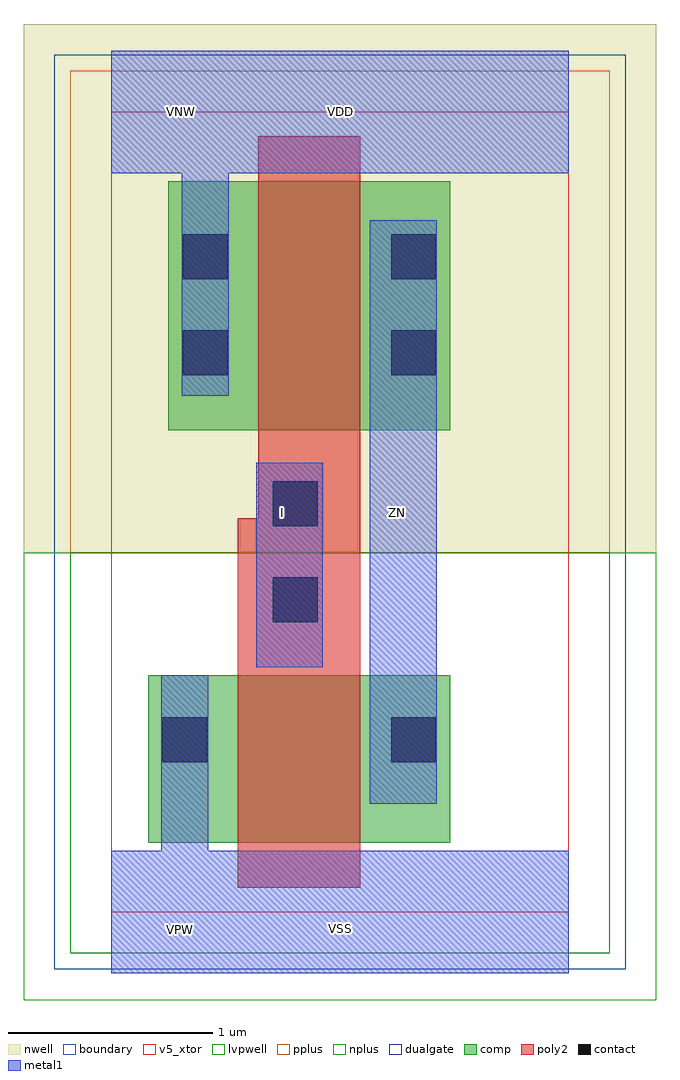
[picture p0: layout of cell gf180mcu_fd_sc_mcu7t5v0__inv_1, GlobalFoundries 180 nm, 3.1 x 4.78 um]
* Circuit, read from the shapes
.subckt gf180mcu_fd_sc_mcu7t5v0__inv_1 I VDD VNW VSS ZN
XM1 ZN I VSS VSUBS nfet_05v0 w=0.82u l=0.6u
XM2 ZN I VDD VNW pfet_05v0 w=1.22u l=0.5u
.ends

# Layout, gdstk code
import gdstk
lib = gdstk.Library(unit=1e-6, precision=5e-09)
def R(c, l, rs):  # rectangles x0, y0, x1, y1
    for r in rs: c.add(gdstk.rectangle(r[:2], r[2:], *l))
def P(c, l, *ps):  # polygons
    for p in ps: c.add(gdstk.Polygon(p, *l))
boundary = (0, 0)
nwell = (21, 0)
comp = (22, 0)
poly2 = (30, 0)
pplus = (31, 0)
nplus = (32, 0)
contact = (33, 0)
metal1 = (34, 0)
dualgate = (55, 0)
v5_xtor = (112, 1)
lvpwell = (204, 0)

gf180mcu_fd_sc_mcu7t5v0_ = lib.new_cell('gf180mcu_fd_sc_mcu7t5v0__inv_1')
R(gf180mcu_fd_sc_mcu7t5v0_, boundary, [(6.915,20.075,9.155,23.995)])
R(gf180mcu_fd_sc_mcu7t5v0_, nwell, [(6.485,21.835,9.585,24.425)])
R(gf180mcu_fd_sc_mcu7t5v0_, comp, [(7.095,20.415,8.575,21.235), (7.195,22.435,8.575,23.655)])
P(gf180mcu_fd_sc_mcu7t5v0_, poly2, [(7.535,20.195),(7.535,22.005),(7.635,22.005),(7.635,23.875),(8.135,23.875),(8.135,20.195)])
R(gf180mcu_fd_sc_mcu7t5v0_, pplus, [(6.715,21.835,9.355,24.195)])
R(gf180mcu_fd_sc_mcu7t5v0_, nplus, [(6.715,19.875,9.355,21.835)])
R(gf180mcu_fd_sc_mcu7t5v0_, contact, [(7.165,20.81,7.385,21.03), (8.285,20.81,8.505,21.03), (7.705,21.495,7.925,21.715), (7.705,21.965,7.925,22.185), (7.265,22.705,7.485,22.925), (8.285,22.705,8.505,22.925), (7.265,23.175,7.485,23.395), (8.285,23.175,8.505,23.395)])
R(gf180mcu_fd_sc_mcu7t5v0_, metal1, [(8.18,20.605,8.51,23.465), (7.625,21.275,7.95,22.275)])
P(gf180mcu_fd_sc_mcu7t5v0_, metal1, [(7.26,22.605),(7.26,23.695),(6.915,23.695),(6.915,24.295),(9.155,24.295),(9.155,23.695),(7.49,23.695),(7.49,22.605)],
  [(6.915,19.775),(6.915,20.375),(7.16,20.375),(7.16,21.235),(7.39,21.235),(7.39,20.375),(9.155,20.375),(9.155,19.775)])
R(gf180mcu_fd_sc_mcu7t5v0_, dualgate, [(6.635,19.795,9.435,24.275)])
R(gf180mcu_fd_sc_mcu7t5v0_, v5_xtor, [(6.915,20.075,9.155,23.995)])
R(gf180mcu_fd_sc_mcu7t5v0_, lvpwell, [(6.485,19.645,9.585,21.835)])
gf180mcu_fd_sc_mcu7t5v0_.add(gdstk.Label('VDD', (8.035,23.995), layer=34, texttype=10))
gf180mcu_fd_sc_mcu7t5v0_.add(gdstk.Label('I', (7.755,22.035), layer=34, texttype=10))
gf180mcu_fd_sc_mcu7t5v0_.add(gdstk.Label('ZN', (8.315,22.035), layer=34, texttype=10))
gf180mcu_fd_sc_mcu7t5v0_.add(gdstk.Label('VSS', (8.035,19.995), layer=34, texttype=10))
gf180mcu_fd_sc_mcu7t5v0_.add(gdstk.Label('VNW', (7.26,23.995), layer=21, texttype=10))
gf180mcu_fd_sc_mcu7t5v0_.add(gdstk.Label('VPW', (7.255,19.99), layer=204, texttype=10))

lib.write_gds('gf180mcu_fd_sc_mcu7t5v0__inv_1.gds')
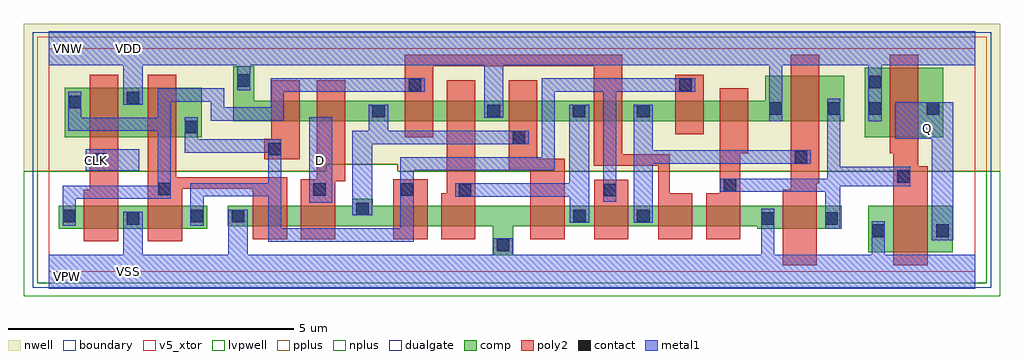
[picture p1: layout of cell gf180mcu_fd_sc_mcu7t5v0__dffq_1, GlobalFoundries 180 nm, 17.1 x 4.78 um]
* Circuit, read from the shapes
.subckt gf180mcu_fd_sc_mcu7t5v0__dffq_1 CLK D Q VDD VNW VSS
XM1 VSS CLK n1 VSUBS nfet_05v0 w=0.405u l=0.6u
XM2 n2 n1 VSS VSUBS nfet_05v0 w=0.405u l=0.6u
XM3 n3 n1 VSS VSUBS nfet_05v0 w=0.36u l=0.6u
XM4 n4 D n3 VSUBS nfet_05v0 w=0.36u l=0.6u
XM5 n5 n2 n4 VSUBS nfet_05v0 w=0.36u l=0.6u
XM6 VSS n6 n5 VSUBS nfet_05v0 w=0.36u l=0.6u
XM7 n6 n4 VSS VSUBS nfet_05v0 w=0.36u l=0.6u
XM8 n7 n2 n6 VSUBS nfet_05v0 w=0.36u l=0.6u
XM9 n8 n1 n7 VSUBS nfet_05v0 w=0.36u l=0.6u
XM10 VSS n9 n8 VSUBS nfet_05v0 w=0.36u l=0.6u
XM11 n9 n7 VSS VSUBS nfet_05v0 w=0.4u l=0.6u
XM12 Q n9 VSS VSUBS nfet_05v0 w=0.82u l=0.6u
XM13 VDD CLK n1 VNW pfet_05v0 w=0.865u l=0.5u
XM14 n2 n1 VDD VNW pfet_05v0 w=0.865u l=0.5u
XM15 n10 n2 VDD VNW pfet_05v0 w=0.36u l=0.5u
XM16 n4 D n10 VNW pfet_05v0 w=0.36u l=0.5u
XM17 n11 n1 n4 VNW pfet_05v0 w=0.36u l=0.5u
XM18 VDD n6 n11 VNW pfet_05v0 w=0.36u l=0.5u
XM19 n6 n4 VDD VNW pfet_05v0 w=0.36u l=0.5u
XM20 n7 n1 n6 VNW pfet_05v0 w=0.36u l=0.5u
XM21 n12 n2 n7 VNW pfet_05v0 w=0.36u l=0.5u
XM22 VDD n9 n12 VNW pfet_05v0 w=0.36u l=0.5u
XM23 n9 n7 VDD VNW pfet_05v0 w=0.8u l=0.5u
XM24 Q n9 VDD VNW pfet_05v0 w=1.22u l=0.5u
.ends

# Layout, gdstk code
import gdstk
lib = gdstk.Library(unit=1e-6, precision=5e-09)
def R(c, l, rs):  # rectangles x0, y0, x1, y1
    for r in rs: c.add(gdstk.rectangle(r[:2], r[2:], *l))
def P(c, l, *ps):  # polygons
    for p in ps: c.add(gdstk.Polygon(p, *l))
boundary = (0, 0)
nwell = (21, 0)
comp = (22, 0)
poly2 = (30, 0)
pplus = (31, 0)
nplus = (32, 0)
contact = (33, 0)
metal1 = (34, 0)
dualgate = (55, 0)
v5_xtor = (112, 1)
lvpwell = (204, 0)

gf180mcu_fd_sc_mcu7t5v0_ = lib.new_cell('gf180mcu_fd_sc_mcu7t5v0__dffq_1')
R(gf180mcu_fd_sc_mcu7t5v0_, boundary, [(-19.37,19.2,-3.13,23.12)])
P(gf180mcu_fd_sc_mcu7t5v0_, nwell, [(-19.8,20.96),(-19.8,23.55),(-2.7,23.55),(-2.7,20.96),(-13.25,20.96),(-13.25,21.085),(-14.505,21.085),(-14.505,20.96)])
R(gf180mcu_fd_sc_mcu7t5v0_, comp, [(-5.01,19.54,-3.53,20.36), (-19.19,19.955,-16.59,20.36), (-19.09,21.56,-16.69,22.425), (-5.07,21.56,-3.69,22.78)])
P(gf180mcu_fd_sc_mcu7t5v0_, comp, [(-16.13,21.835),(-16.13,22.8),(-15.77,22.8),(-15.77,22.195),(-6.81,22.195),(-6.81,22.635),(-5.43,22.635),(-5.43,21.835)],
  [(-11.59,19.49),(-11.59,19.995),(-16.23,19.995),(-16.23,20.355),(-14.05,20.355),(-14.05,20.485),(-13.69,20.485),(-13.69,20.355),(-5.47,20.355),(-5.47,19.955),(-6.95,19.955),(-6.95,19.995),(-11.23,19.995),(-11.23,19.49)])
R(gf180mcu_fd_sc_mcu7t5v0_, poly2, [(-13.33,19.775,-12.73,20.82), (-9.81,19.775,-9.21,20.815), (-8.39,21.615,-7.89,22.655)])
P(gf180mcu_fd_sc_mcu7t5v0_, poly2, [(-4.57,19.32),(-4.57,21.28),(-4.63,21.28),(-4.63,23),(-4.13,23),(-4.13,21.05),(-3.97,21.05),(-3.97,19.32)],
  [(-6.51,19.32),(-6.51,20.64),(-6.37,20.64),(-6.37,23),(-5.87,23),(-5.87,20.755),(-5.91,20.755),(-5.91,19.32)],
  [(-7.85,19.775),(-7.85,20.575),(-7.61,20.575),(-7.61,22.415),(-7.11,22.415),(-7.11,21.28),(-7.25,21.28),(-7.25,19.775)],
  [(-8.69,19.775),(-8.69,21.06),(-9.815,21.06),(-9.815,22.8),(-12.63,22.8),(-12.63,21.555),(-13.13,21.555),(-13.13,23),(-9.315,23),(-9.315,21.26),(-8.49,21.26),(-8.49,20.575),(-8.09,20.575),(-8.09,19.775)],
  [(-10.93,19.775),(-10.93,20.98),(-11.31,20.98),(-11.31,22.56),(-10.81,22.56),(-10.81,21.18),(-10.33,21.18),(-10.33,19.775)],
  [(-12.49,19.775),(-12.49,20.575),(-12.39,20.575),(-12.39,22.56),(-11.89,22.56),(-11.89,19.775)],
  [(-14.95,19.775),(-14.95,20.82),(-14.67,20.82),(-14.67,22.56),(-14.17,22.56),(-14.17,20.785),(-14.35,20.785),(-14.35,19.775)],
  [(-15.59,21.175),(-15.59,21.535),(-15.47,21.535),(-15.47,22.56),(-14.97,22.56),(-14.97,21.175)],
  [(-17.63,19.735),(-17.63,22.65),(-17.13,22.65),(-17.13,20.86),(-15.19,20.86),(-15.19,19.775),(-15.79,19.775),(-15.79,20.66),(-17.03,20.66),(-17.03,19.735)],
  [(-18.75,19.735),(-18.75,20.64),(-18.65,20.64),(-18.65,22.65),(-18.15,22.65),(-18.15,19.735)])
P(gf180mcu_fd_sc_mcu7t5v0_, pplus, [(-19.57,20.96),(-19.57,23.32),(-2.93,23.32),(-2.93,20.96),(-13.25,20.96),(-13.25,21.085),(-14.505,21.085),(-14.505,20.96)])
P(gf180mcu_fd_sc_mcu7t5v0_, nplus, [(-19.57,19),(-19.57,20.96),(-14.505,20.96),(-14.505,21.085),(-13.25,21.085),(-13.25,20.96),(-2.93,20.96),(-2.93,19)])
R(gf180mcu_fd_sc_mcu7t5v0_, contact, [(-11.52,19.56,-11.3,19.78), (-4.94,19.81,-4.72,20.03), (-3.82,19.81,-3.6,20.03), (-18,20.025,-17.78,20.245), (-6.88,20.025,-6.66,20.245), (-5.76,20.025,-5.54,20.245), (-16.16,20.065,-15.94,20.285), (-10.18,20.065,-9.96,20.285), (-9.06,20.065,-8.84,20.285), (-19.12,20.07,-18.9,20.29), (-16.88,20.07,-16.66,20.29), (-13.98,20.195,-13.76,20.415), (-12.18,20.525,-11.96,20.745), (-9.645,20.525,-9.425,20.745), (-14.735,20.53,-14.515,20.75), (-13.2,20.53,-12.98,20.75), (-17.45,20.54,-17.23,20.76), (-7.54,20.605,-7.32,20.825), (-4.5,20.76,-4.28,20.98), (-18.58,21.055,-18.36,21.275), (-6.3,21.1,-6.08,21.32), (-15.52,21.245,-15.3,21.465), (-11.24,21.445,-11.02,21.665), (-16.98,21.63,-16.76,21.85), (-13.7,21.905,-13.48,22.125), (-11.68,21.905,-11.46,22.125), (-10.185,21.905,-9.965,22.125), (-9.06,21.905,-8.84,22.125), (-6.74,21.95,-6.52,22.17), (-5.72,21.95,-5.5,22.17), (-5,21.95,-4.78,22.17), (-3.98,21.95,-3.76,22.17), (-19.02,22.07,-18.8,22.29), (-18,22.135,-17.78,22.355), (-13.06,22.365,-12.84,22.585), (-8.32,22.365,-8.1,22.585), (-5,22.42,-4.78,22.64), (-16.06,22.445,-15.84,22.665)])
R(gf180mcu_fd_sc_mcu7t5v0_, metal1, [(-14.8,20.41,-14.395,21.91), (-18.72,20.97,-17.78,21.35)])
P(gf180mcu_fd_sc_mcu7t5v0_, metal1, [(-6.745,21.835),(-6.745,22.82),(-11.4,22.82),(-11.4,21.9),(-11.74,21.9),(-11.74,22.82),(-15.835,22.82),(-15.835,22.385),(-16.065,22.385),(-16.065,22.82),(-17.72,22.82),(-17.72,22.13),(-18.06,22.13),(-18.06,22.82),(-19.37,22.82),(-19.37,23.42),(-3.13,23.42),(-3.13,22.82),(-4.775,22.82),(-4.775,21.835),(-5.005,21.835),(-5.005,22.82),(-6.515,22.82),(-6.515,21.835)],
  [(-19.37,18.9),(-19.37,19.5),(-18.06,19.5),(-18.06,20.25),(-17.72,20.25),(-17.72,19.5),(-16.22,19.5),(-16.22,20.29),(-15.88,20.29),(-15.88,19.5),(-11.58,19.5),(-11.58,19.785),(-11.24,19.785),(-11.24,19.5),(-6.885,19.5),(-6.885,20.305),(-6.655,20.305),(-6.655,19.5),(-4.945,19.5),(-4.945,20.09),(-4.715,20.09),(-4.715,19.5),(-3.13,19.5),(-3.13,18.9)],
  [(-3.9,19.75),(-3.9,21.53),(-4.535,21.53),(-4.535,22.175),(-3.52,22.175),(-3.52,19.75)],
  [(-5.765,19.955),(-5.765,20.6),(-7.6,20.6),(-7.6,20.83),(-5.725,20.83),(-5.725,22.23),(-5.495,22.23),(-5.495,21.04),(-4.275,21.04),(-4.275,20.7),(-5.5,20.7),(-5.5,19.955)],
  [(-9.12,20.06),(-9.12,22.13),(-8.78,22.13),(-8.78,21.33),(-6.02,21.33),(-6.02,21.095),(-8.78,21.095),(-8.78,20.06)],
  [(-15.525,19.73),(-15.525,20.525),(-16.655,20.525),(-16.655,20.01),(-16.885,20.01),(-16.885,20.755),(-15.525,20.755),(-15.525,21.29),(-16.985,21.29),(-16.985,21.91),(-16.755,21.91),(-16.755,21.525),(-15.295,21.525),(-15.295,19.96),(-13.205,19.96),(-13.205,21.21),(-10.73,21.21),(-10.73,22.59),(-8.04,22.59),(-8.04,22.36),(-9.42,22.36),(-9.42,20.425),(-9.65,20.425),(-9.65,22.36),(-10.5,22.36),(-10.5,20.98),(-12.975,20.98),(-12.975,19.73)],
  [(-10.24,20.06),(-10.24,20.52),(-12.24,20.52),(-12.24,20.75),(-10.245,20.75),(-10.245,22.13),(-9.9,22.13),(-9.9,20.06)],
  [(-14.045,20.19),(-14.045,21.67),(-13.76,21.67),(-13.76,22.13),(-13.42,22.13),(-13.42,21.67),(-10.96,21.67),(-10.96,21.44),(-13.7,21.44),(-13.7,20.19)],
  [(-19.125,20.01),(-19.125,20.71),(-17.455,20.71),(-17.455,21.67),(-19.025,21.67),(-19.025,22.355),(-18.795,22.355),(-18.795,21.9),(-17.455,21.9),(-17.455,22.415),(-16.295,22.415),(-16.295,22.085),(-15.48,22.085),(-15.48,22.59),(-12.78,22.59),(-12.78,22.36),(-15.25,22.36),(-15.25,21.85),(-16.525,21.85),(-16.525,22.18),(-17.225,22.18),(-17.225,20.48),(-18.895,20.48),(-18.895,20.01)])
R(gf180mcu_fd_sc_mcu7t5v0_, dualgate, [(-19.65,18.92,-2.85,23.4)])
R(gf180mcu_fd_sc_mcu7t5v0_, v5_xtor, [(-19.37,19.2,-3.13,23.12)])
P(gf180mcu_fd_sc_mcu7t5v0_, lvpwell, [(-19.8,18.77),(-19.8,20.96),(-14.505,20.96),(-14.505,21.085),(-13.25,21.085),(-13.25,20.96),(-2.7,20.96),(-2.7,18.77)])
gf180mcu_fd_sc_mcu7t5v0_.add(gdstk.Label('D', (-14.61,21.16), layer=34, texttype=10))
gf180mcu_fd_sc_mcu7t5v0_.add(gdstk.Label('VSS', (-17.97,19.2), layer=34, texttype=10))
gf180mcu_fd_sc_mcu7t5v0_.add(gdstk.Label('CLK', (-18.53,21.16), layer=34, texttype=10))
gf180mcu_fd_sc_mcu7t5v0_.add(gdstk.Label('Q', (-3.97,21.72), layer=34, texttype=10))
gf180mcu_fd_sc_mcu7t5v0_.add(gdstk.Label('VDD', (-17.97,23.12), layer=34, texttype=10))
gf180mcu_fd_sc_mcu7t5v0_.add(gdstk.Label('VNW', (-19.025,23.12), layer=21, texttype=10))
gf180mcu_fd_sc_mcu7t5v0_.add(gdstk.Label('VPW', (-19.03,19.115), layer=204, texttype=10))

lib.write_gds('gf180mcu_fd_sc_mcu7t5v0__dffq_1.gds')
